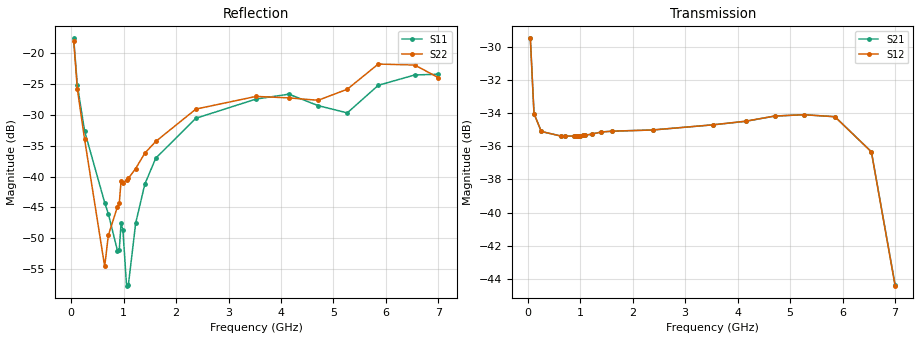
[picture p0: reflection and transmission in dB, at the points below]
! Integrated Device Technology
! Corporate Headquarters
! 6024 Silver Creek Valley Road
! San Jose, CA 95138  USA
! Phone:  1-408-284-8200
! Toll Free:  1-800-223-1366
! Webpage:  http://www.idt.com/
! Timing and RF Division
! 515 Groton Road, Suite 102
! Westford, MA 01886-6024
! Device:  F2258
! Description: Voltage Variable RF Attenuator
! Frequency:  50.0 -  6000.00 MHz
! Package:  3x3 mm Thin QFN Plastic Package: 16 pin
! Ports:  2 RF, 2 DC
!  Pin  1  = NC
!  Pin  2  = NC
!  Pin  3  = RF2  = Port 2
!  Pin  4  = GND
!  Pin  5  = Vdd
!  Pin  6  = NC
!  Pin  7  = VCTRL
!  Pin  8  = NC
!  Pin  9  = GND
!  Pin 10  = RF1  = Port 1
!  Pin 11  = NC
!  Pin 12  = NC
!  Pin 13  = NC
!  Pin 14  = NC
!  Pin 15  = NC
!  Pin 16  = NC
! Vcntrl:  2.220 Volts
! Vdd:  +3.300 Volts
! Current:  1.152 mA
! Data:  The device was measured on a the F2258 evaluation board which has
!  individual transmission lines to the RF pins.  Data was collected
!  using a calibrated network analyzer.  The evaluation board was
!  de-embedded using a TRL calibration technique.
!  The reference plane is the edge of the package pin.
! Misc:  SN 10
!  Action Tracker AT0285
! Date Measured:  2014-12-10
! Date:  2016-01-13  MJV
! Note:
!  Integrated Device Technology supplies this data as a sample of measured
!  data at the package pin for this product.  Your particular data for this
!  product may vary.
!  Data was taken at 25 degrees C.
!  Integrated Device Technology reserves the right to change this data at anytime.
!Freq_(GHz)  S11M_(dB)  S11P_(deg)  S21M_(dB)  S21P_(deg)  S12M_(dB)  S12P_(deg)  S22M_(dB)  S22P_(deg)
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# GHz S dB R 50
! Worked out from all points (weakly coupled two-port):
!   201 points, 50 MHz to 7 GHz, reference 50 ohm
!   highest |S21| = -29.50 dB at 50 MHz (marker M1); lowest = -44.3 dB at 7 GHz (marker M2)
!   lowest |S11| = -57.7 dB at 1.058 GHz (marker M3), VSWR 1.00, Z = 49.9 + j0.053 ohm
!   |S11| at or under -10 dB: start of sweep to end of sweep
!   |S22| runs from -54.6 to -17.9 dB; largest |S21 - S12| = 7.9e-05
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0.05  -17.56 -111.0  -29.50 -68.3  -29.50 -68.3  -17.91 -111.0
0.1195  -25.12 -106.9  -34.03 -36.8  -34.03 -36.8  -25.77 -105.8
0.2585  -32.62 -111.8  -35.11 -18.7  -35.11 -18.8  -33.96 -109.5
0.64075  -44.22 -127.6  -35.39 -9.7  -35.39 -9.7  -54.58 163.2
0.71025  -46.02 -137.8  -35.39 -9.2  -35.39 -9.2  -49.53 121.0
0.884  -52.04 166.1  -35.39 -8.4  -35.38 -8.5  -44.89 106.5
0.91875  -51.87 150.2  -35.38 -8.4  -35.38 -8.4  -44.34 104.9
0.9535  -47.48 -162.8  -35.39 -8.2  -35.39 -8.2  -40.64 115.4
0.98825  -48.70 -174.9  -35.37 -8.1  -35.37 -8.2  -40.98 113.2
1.05775  -57.70 156.0  -35.35 -8.0  -35.35 -8.0  -40.56 97.5
1.0925  -57.56 119.2  -35.34 -7.9  -35.34 -7.9  -40.28 93.9
1.2315  -47.55 47.3  -35.26 -8.0  -35.26 -8.0  -38.69 72.5
1.40525  -41.23 33.9  -35.14 -8.6  -35.14 -8.6  -36.19 60.9
1.61375  -37.01 32.8  -35.09 -9.7  -35.09 -9.6  -34.29 49.2
2.37825  -30.53 48.1  -35.02 -13.3  -35.02 -13.3  -29.04 41.3
3.525  -27.41 91.6  -34.71 -19.7  -34.71 -19.7  -26.98 66.0
4.1505  -26.62 105.0  -34.50 -24.2  -34.49 -24.2  -27.22 73.9
4.7065  -28.47 95.6  -34.18 -28.9  -34.18 -28.9  -27.61 57.3
5.2625  -29.66 54.3  -34.10 -35.1  -34.10 -35.1  -25.82 19.9
5.85325  -25.18 29.8  -34.22 -45.6  -34.22 -45.6  -21.73 -3.3
6.54825  -23.50 45.1  -36.33 -66.3  -36.34 -66.4  -21.88 -38.3
7  -23.38 84.5  -44.33 -62.0  -44.40 -61.4  -23.94 -129.7
